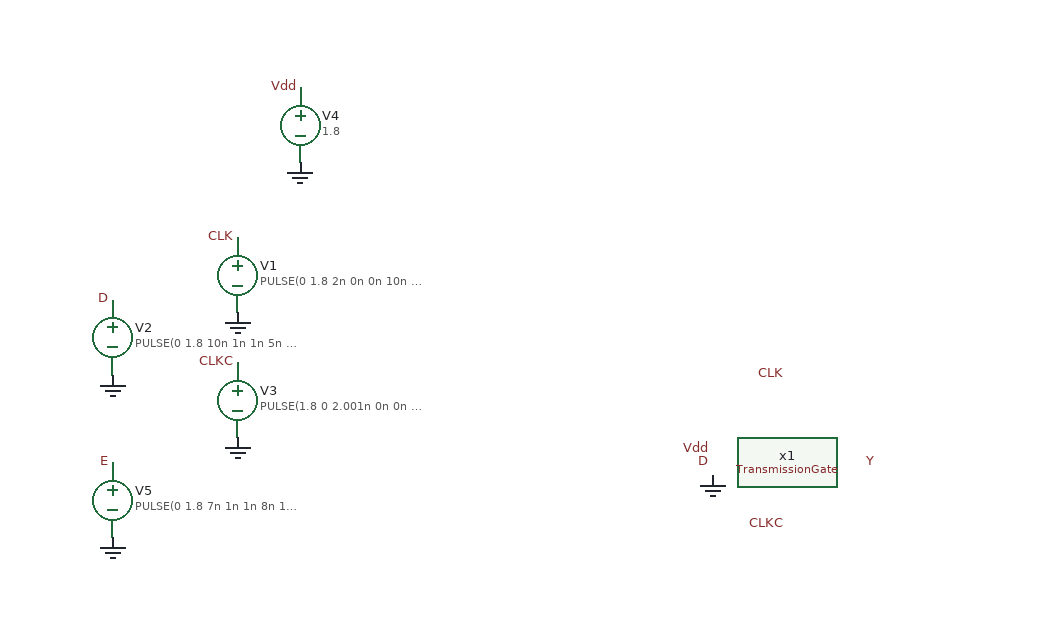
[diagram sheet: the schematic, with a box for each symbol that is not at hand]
v {xschem version=3.4.8RC file_version=1.2}
G {}
K {}
V {}
S {}
E {}
C {vsource.sym} -580 -380 0 0 {name=V1 value="PULSE(0 1.8 2n 0n 0n 10n 20n)" savecurrent=false}
C {vsource.sym} -680 -330 0 1 {name=V2 value="PULSE(0 1.8 10n 1n 1n 5n 10n)"  savecurrent=false}
C {vsource.sym} -580 -280 0 0 {name=V3 value="PULSE(1.8 0 2.001n 0n 0n 10n 20n)"  savecurrent=false}
C {lab_pin.sym} -580 -410 0 0 {name=p1 sig_type=std_logic lab=CLK}
C {lab_pin.sym} -680 -360 0 0 {name=p2 sig_type=std_logic lab=D}
C {lab_pin.sym} -580 -310 0 0 {name=p3 sig_type=std_logic lab=CLKC}
C {gnd.sym} -680 -300 0 0 {name=l1 lab=GND}
C {gnd.sym} -580 -350 0 0 {name=l2 lab=GND}
C {gnd.sym} -580 -250 0 0 {name=l3 lab=GND}
C {vsource.sym} -530 -500 0 0 {name=V4 value=1.8 savecurrent=false}
C {lab_pin.sym} -530 -530 0 0 {name=p8 sig_type=std_logic lab=Vdd}
C {gnd.sym} -530 -470 0 0 {name=l6 lab=GND}
C {vsource.sym} -680 -200 0 1 {name=V5 value="PULSE(0 1.8 7n 1n 1n 8n 16n)"  savecurrent=false}
C {lab_pin.sym} -680 -230 0 0 {name=p11 sig_type=std_logic lab=E}
C {gnd.sym} -680 -170 0 0 {name=l7 lab=GND}
C {lab_pin.sym} -140 -300 0 0 {name=p4 sig_type=std_logic lab=CLK}
C {lab_pin.sym} -140 -180 0 0 {name=p5 sig_type=std_logic lab=CLKC}
C {lab_pin.sym} -200 -230 0 0 {name=p6 sig_type=std_logic lab=D}
C {lab_pin.sym} -200 -240 1 0 {name=p7 sig_type=std_logic lab=Vdd}
C {gnd.sym} -200 -220 1 0 {name=l4 lab=GND}
C {lab_pin.sym} -80 -230 0 1 {name=p9 sig_type=std_logic lab=Y}
C {/home/safal/projects/GitHub_CMOS_4bit_ALU/AllSymbols/GenericSym/TransmissionGate.sym} -140 -230 0 0 {name=x1}
